VERSION 5.7 ;
BUSBITCHARS "[]" ;
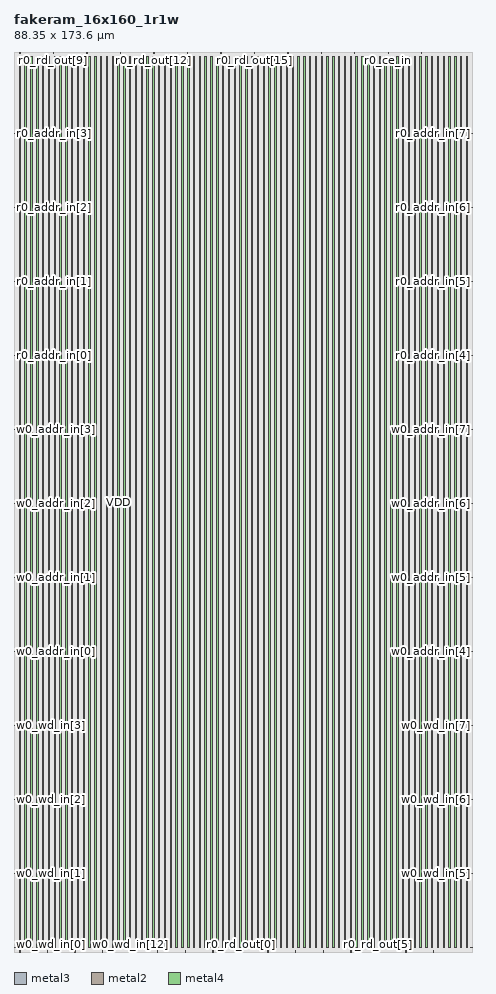
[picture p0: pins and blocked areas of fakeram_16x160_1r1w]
MACRO fakeram_16x160_1r1w
  FOREIGN fakeram_16x160_1r1w 0 0 ;
  SYMMETRY X Y R90 ;
  SIZE 88.350 BY 173.600 ;
  CLASS BLOCK ;
  PIN w0_wd_in[0]
    DIRECTION INPUT ;
    USE SIGNAL ;
    SHAPE ABUTMENT ;
    PORT
      LAYER metal3 ;
      RECT 0.000 0.805 0.210 0.875 ;
    END
  END w0_wd_in[0]
  PIN w0_wd_in[1]
    DIRECTION INPUT ;
    USE SIGNAL ;
    SHAPE ABUTMENT ;
    PORT
      LAYER metal3 ;
      RECT 0.000 15.085 0.210 15.155 ;
    END
  END w0_wd_in[1]
  PIN w0_wd_in[2]
    DIRECTION INPUT ;
    USE SIGNAL ;
    SHAPE ABUTMENT ;
    PORT
      LAYER metal3 ;
      RECT 0.000 29.365 0.210 29.435 ;
    END
  END w0_wd_in[2]
  PIN w0_wd_in[3]
    DIRECTION INPUT ;
    USE SIGNAL ;
    SHAPE ABUTMENT ;
    PORT
      LAYER metal3 ;
      RECT 0.000 43.645 0.210 43.715 ;
    END
  END w0_wd_in[3]
  PIN w0_wd_in[4]
    DIRECTION INPUT ;
    USE SIGNAL ;
    SHAPE ABUTMENT ;
    PORT
      LAYER metal3 ;
      RECT 88.140 0.805 88.350 0.875 ;
    END
  END w0_wd_in[4]
  PIN w0_wd_in[5]
    DIRECTION INPUT ;
    USE SIGNAL ;
    SHAPE ABUTMENT ;
    PORT
      LAYER metal3 ;
      RECT 88.140 15.085 88.350 15.155 ;
    END
  END w0_wd_in[5]
  PIN w0_wd_in[6]
    DIRECTION INPUT ;
    USE SIGNAL ;
    SHAPE ABUTMENT ;
    PORT
      LAYER metal3 ;
      RECT 88.140 29.365 88.350 29.435 ;
    END
  END w0_wd_in[6]
  PIN w0_wd_in[7]
    DIRECTION INPUT ;
    USE SIGNAL ;
    SHAPE ABUTMENT ;
    PORT
      LAYER metal3 ;
      RECT 88.140 43.645 88.350 43.715 ;
    END
  END w0_wd_in[7]
  PIN w0_wd_in[8]
    DIRECTION INPUT ;
    USE SIGNAL ;
    SHAPE ABUTMENT ;
    PORT
      LAYER metal2 ;
      RECT 1.105 0.000 1.175 0.210 ;
    END
  END w0_wd_in[8]
  PIN w0_wd_in[9]
    DIRECTION INPUT ;
    USE SIGNAL ;
    SHAPE ABUTMENT ;
    PORT
      LAYER metal2 ;
      RECT 6.425 0.000 6.495 0.210 ;
    END
  END w0_wd_in[9]
  PIN w0_wd_in[10]
    DIRECTION INPUT ;
    USE SIGNAL ;
    SHAPE ABUTMENT ;
    PORT
      LAYER metal2 ;
      RECT 11.745 0.000 11.815 0.210 ;
    END
  END w0_wd_in[10]
  PIN w0_wd_in[11]
    DIRECTION INPUT ;
    USE SIGNAL ;
    SHAPE ABUTMENT ;
    PORT
      LAYER metal2 ;
      RECT 17.065 0.000 17.135 0.210 ;
    END
  END w0_wd_in[11]
  PIN w0_wd_in[12]
    DIRECTION INPUT ;
    USE SIGNAL ;
    SHAPE ABUTMENT ;
    PORT
      LAYER metal2 ;
      RECT 22.385 0.000 22.455 0.210 ;
    END
  END w0_wd_in[12]
  PIN w0_wd_in[13]
    DIRECTION INPUT ;
    USE SIGNAL ;
    SHAPE ABUTMENT ;
    PORT
      LAYER metal2 ;
      RECT 27.705 0.000 27.775 0.210 ;
    END
  END w0_wd_in[13]
  PIN w0_wd_in[14]
    DIRECTION INPUT ;
    USE SIGNAL ;
    SHAPE ABUTMENT ;
    PORT
      LAYER metal2 ;
      RECT 33.025 0.000 33.095 0.210 ;
    END
  END w0_wd_in[14]
  PIN w0_wd_in[15]
    DIRECTION INPUT ;
    USE SIGNAL ;
    SHAPE ABUTMENT ;
    PORT
      LAYER metal2 ;
      RECT 38.345 0.000 38.415 0.210 ;
    END
  END w0_wd_in[15]
  PIN r0_rd_out[0]
    DIRECTION OUTPUT ;
    USE SIGNAL ;
    SHAPE ABUTMENT ;
    PORT
      LAYER metal2 ;
      RECT 43.665 0.000 43.735 0.210 ;
    END
  END r0_rd_out[0]
  PIN r0_rd_out[1]
    DIRECTION OUTPUT ;
    USE SIGNAL ;
    SHAPE ABUTMENT ;
    PORT
      LAYER metal2 ;
      RECT 48.985 0.000 49.055 0.210 ;
    END
  END r0_rd_out[1]
  PIN r0_rd_out[2]
    DIRECTION OUTPUT ;
    USE SIGNAL ;
    SHAPE ABUTMENT ;
    PORT
      LAYER metal2 ;
      RECT 54.305 0.000 54.375 0.210 ;
    END
  END r0_rd_out[2]
  PIN r0_rd_out[3]
    DIRECTION OUTPUT ;
    USE SIGNAL ;
    SHAPE ABUTMENT ;
    PORT
      LAYER metal2 ;
      RECT 59.625 0.000 59.695 0.210 ;
    END
  END r0_rd_out[3]
  PIN r0_rd_out[4]
    DIRECTION OUTPUT ;
    USE SIGNAL ;
    SHAPE ABUTMENT ;
    PORT
      LAYER metal2 ;
      RECT 64.945 0.000 65.015 0.210 ;
    END
  END r0_rd_out[4]
  PIN r0_rd_out[5]
    DIRECTION OUTPUT ;
    USE SIGNAL ;
    SHAPE ABUTMENT ;
    PORT
      LAYER metal2 ;
      RECT 70.265 0.000 70.335 0.210 ;
    END
  END r0_rd_out[5]
  PIN r0_rd_out[6]
    DIRECTION OUTPUT ;
    USE SIGNAL ;
    SHAPE ABUTMENT ;
    PORT
      LAYER metal2 ;
      RECT 75.585 0.000 75.655 0.210 ;
    END
  END r0_rd_out[6]
  PIN r0_rd_out[7]
    DIRECTION OUTPUT ;
    USE SIGNAL ;
    SHAPE ABUTMENT ;
    PORT
      LAYER metal2 ;
      RECT 80.905 0.000 80.975 0.210 ;
    END
  END r0_rd_out[7]
  PIN r0_rd_out[8]
    DIRECTION OUTPUT ;
    USE SIGNAL ;
    SHAPE ABUTMENT ;
    PORT
      LAYER metal2 ;
      RECT 1.105 173.390 1.175 173.600 ;
    END
  END r0_rd_out[8]
  PIN r0_rd_out[9]
    DIRECTION OUTPUT ;
    USE SIGNAL ;
    SHAPE ABUTMENT ;
    PORT
      LAYER metal2 ;
      RECT 7.565 173.390 7.635 173.600 ;
    END
  END r0_rd_out[9]
  PIN r0_rd_out[10]
    DIRECTION OUTPUT ;
    USE SIGNAL ;
    SHAPE ABUTMENT ;
    PORT
      LAYER metal2 ;
      RECT 14.025 173.390 14.095 173.600 ;
    END
  END r0_rd_out[10]
  PIN r0_rd_out[11]
    DIRECTION OUTPUT ;
    USE SIGNAL ;
    SHAPE ABUTMENT ;
    PORT
      LAYER metal2 ;
      RECT 20.485 173.390 20.555 173.600 ;
    END
  END r0_rd_out[11]
  PIN r0_rd_out[12]
    DIRECTION OUTPUT ;
    USE SIGNAL ;
    SHAPE ABUTMENT ;
    PORT
      LAYER metal2 ;
      RECT 26.945 173.390 27.015 173.600 ;
    END
  END r0_rd_out[12]
  PIN r0_rd_out[13]
    DIRECTION OUTPUT ;
    USE SIGNAL ;
    SHAPE ABUTMENT ;
    PORT
      LAYER metal2 ;
      RECT 33.405 173.390 33.475 173.600 ;
    END
  END r0_rd_out[13]
  PIN r0_rd_out[14]
    DIRECTION OUTPUT ;
    USE SIGNAL ;
    SHAPE ABUTMENT ;
    PORT
      LAYER metal2 ;
      RECT 39.865 173.390 39.935 173.600 ;
    END
  END r0_rd_out[14]
  PIN r0_rd_out[15]
    DIRECTION OUTPUT ;
    USE SIGNAL ;
    SHAPE ABUTMENT ;
    PORT
      LAYER metal2 ;
      RECT 46.325 173.390 46.395 173.600 ;
    END
  END r0_rd_out[15]
  PIN w0_addr_in[0]
    DIRECTION INPUT ;
    USE SIGNAL ;
    SHAPE ABUTMENT ;
    PORT
      LAYER metal3 ;
      RECT 0.000 57.925 0.210 57.995 ;
    END
  END w0_addr_in[0]
  PIN w0_addr_in[1]
    DIRECTION INPUT ;
    USE SIGNAL ;
    SHAPE ABUTMENT ;
    PORT
      LAYER metal3 ;
      RECT 0.000 72.205 0.210 72.275 ;
    END
  END w0_addr_in[1]
  PIN w0_addr_in[2]
    DIRECTION INPUT ;
    USE SIGNAL ;
    SHAPE ABUTMENT ;
    PORT
      LAYER metal3 ;
      RECT 0.000 86.485 0.210 86.555 ;
    END
  END w0_addr_in[2]
  PIN w0_addr_in[3]
    DIRECTION INPUT ;
    USE SIGNAL ;
    SHAPE ABUTMENT ;
    PORT
      LAYER metal3 ;
      RECT 0.000 100.765 0.210 100.835 ;
    END
  END w0_addr_in[3]
  PIN w0_addr_in[4]
    DIRECTION INPUT ;
    USE SIGNAL ;
    SHAPE ABUTMENT ;
    PORT
      LAYER metal3 ;
      RECT 88.140 57.925 88.350 57.995 ;
    END
  END w0_addr_in[4]
  PIN w0_addr_in[5]
    DIRECTION INPUT ;
    USE SIGNAL ;
    SHAPE ABUTMENT ;
    PORT
      LAYER metal3 ;
      RECT 88.140 72.205 88.350 72.275 ;
    END
  END w0_addr_in[5]
  PIN w0_addr_in[6]
    DIRECTION INPUT ;
    USE SIGNAL ;
    SHAPE ABUTMENT ;
    PORT
      LAYER metal3 ;
      RECT 88.140 86.485 88.350 86.555 ;
    END
  END w0_addr_in[6]
  PIN w0_addr_in[7]
    DIRECTION INPUT ;
    USE SIGNAL ;
    SHAPE ABUTMENT ;
    PORT
      LAYER metal3 ;
      RECT 88.140 100.765 88.350 100.835 ;
    END
  END w0_addr_in[7]
  PIN r0_addr_in[0]
    DIRECTION INPUT ;
    USE SIGNAL ;
    SHAPE ABUTMENT ;
    PORT
      LAYER metal3 ;
      RECT 0.000 115.045 0.210 115.115 ;
    END
  END r0_addr_in[0]
  PIN r0_addr_in[1]
    DIRECTION INPUT ;
    USE SIGNAL ;
    SHAPE ABUTMENT ;
    PORT
      LAYER metal3 ;
      RECT 0.000 129.325 0.210 129.395 ;
    END
  END r0_addr_in[1]
  PIN r0_addr_in[2]
    DIRECTION INPUT ;
    USE SIGNAL ;
    SHAPE ABUTMENT ;
    PORT
      LAYER metal3 ;
      RECT 0.000 143.605 0.210 143.675 ;
    END
  END r0_addr_in[2]
  PIN r0_addr_in[3]
    DIRECTION INPUT ;
    USE SIGNAL ;
    SHAPE ABUTMENT ;
    PORT
      LAYER metal3 ;
      RECT 0.000 157.885 0.210 157.955 ;
    END
  END r0_addr_in[3]
  PIN r0_addr_in[4]
    DIRECTION INPUT ;
    USE SIGNAL ;
    SHAPE ABUTMENT ;
    PORT
      LAYER metal3 ;
      RECT 88.140 115.045 88.350 115.115 ;
    END
  END r0_addr_in[4]
  PIN r0_addr_in[5]
    DIRECTION INPUT ;
    USE SIGNAL ;
    SHAPE ABUTMENT ;
    PORT
      LAYER metal3 ;
      RECT 88.140 129.325 88.350 129.395 ;
    END
  END r0_addr_in[5]
  PIN r0_addr_in[6]
    DIRECTION INPUT ;
    USE SIGNAL ;
    SHAPE ABUTMENT ;
    PORT
      LAYER metal3 ;
      RECT 88.140 143.605 88.350 143.675 ;
    END
  END r0_addr_in[6]
  PIN r0_addr_in[7]
    DIRECTION INPUT ;
    USE SIGNAL ;
    SHAPE ABUTMENT ;
    PORT
      LAYER metal3 ;
      RECT 88.140 157.885 88.350 157.955 ;
    END
  END r0_addr_in[7]
  PIN w0_we_in
    DIRECTION INPUT ;
    USE SIGNAL ;
    SHAPE ABUTMENT ;
    PORT
      LAYER metal2 ;
      RECT 52.785 173.390 52.855 173.600 ;
    END
  END w0_we_in
  PIN w0_ce_in
    DIRECTION INPUT ;
    USE SIGNAL ;
    SHAPE ABUTMENT ;
    PORT
      LAYER metal2 ;
      RECT 59.245 173.390 59.315 173.600 ;
    END
  END w0_ce_in
  PIN w0_clk
    DIRECTION INPUT ;
    USE SIGNAL ;
    SHAPE ABUTMENT ;
    PORT
      LAYER metal2 ;
      RECT 65.705 173.390 65.775 173.600 ;
    END
  END w0_clk
  PIN r0_ce_in
    DIRECTION INPUT ;
    USE SIGNAL ;
    SHAPE ABUTMENT ;
    PORT
      LAYER metal2 ;
      RECT 72.165 173.390 72.235 173.600 ;
    END
  END r0_ce_in
  PIN r0_clk
    DIRECTION INPUT ;
    USE SIGNAL ;
    SHAPE ABUTMENT ;
    PORT
      LAYER metal2 ;
      RECT 78.625 173.390 78.695 173.600 ;
    END
  END r0_clk
  PIN VSS
    DIRECTION INOUT ;
    USE GROUND ;
    PORT
      LAYER metal4 ;
      RECT 1.000 0.840 1.280 172.760 ;
      RECT 3.240 0.840 3.520 172.760 ;
      RECT 5.480 0.840 5.760 172.760 ;
      RECT 7.720 0.840 8.000 172.760 ;
      RECT 9.960 0.840 10.240 172.760 ;
      RECT 12.200 0.840 12.480 172.760 ;
      RECT 14.440 0.840 14.720 172.760 ;
      RECT 16.680 0.840 16.960 172.760 ;
      RECT 18.920 0.840 19.200 172.760 ;
      RECT 21.160 0.840 21.440 172.760 ;
      RECT 23.400 0.840 23.680 172.760 ;
      RECT 25.640 0.840 25.920 172.760 ;
      RECT 27.880 0.840 28.160 172.760 ;
      RECT 30.120 0.840 30.400 172.760 ;
      RECT 32.360 0.840 32.640 172.760 ;
      RECT 34.600 0.840 34.880 172.760 ;
      RECT 36.840 0.840 37.120 172.760 ;
      RECT 39.080 0.840 39.360 172.760 ;
      RECT 41.320 0.840 41.600 172.760 ;
      RECT 43.560 0.840 43.840 172.760 ;
      RECT 45.800 0.840 46.080 172.760 ;
      RECT 48.040 0.840 48.320 172.760 ;
      RECT 50.280 0.840 50.560 172.760 ;
      RECT 52.520 0.840 52.800 172.760 ;
      RECT 54.760 0.840 55.040 172.760 ;
      RECT 57.000 0.840 57.280 172.760 ;
      RECT 59.240 0.840 59.520 172.760 ;
      RECT 61.480 0.840 61.760 172.760 ;
      RECT 63.720 0.840 64.000 172.760 ;
      RECT 65.960 0.840 66.240 172.760 ;
      RECT 68.200 0.840 68.480 172.760 ;
      RECT 70.440 0.840 70.720 172.760 ;
      RECT 72.680 0.840 72.960 172.760 ;
      RECT 74.920 0.840 75.200 172.760 ;
      RECT 77.160 0.840 77.440 172.760 ;
      RECT 79.400 0.840 79.680 172.760 ;
      RECT 81.640 0.840 81.920 172.760 ;
      RECT 83.880 0.840 84.160 172.760 ;
      RECT 86.120 0.840 86.400 172.760 ;
    END
  END VSS
  PIN VDD
    DIRECTION INOUT ;
    USE POWER ;
    PORT
      LAYER metal4 ;
      RECT 2.120 0.840 2.400 172.760 ;
      RECT 4.360 0.840 4.640 172.760 ;
      RECT 6.600 0.840 6.880 172.760 ;
      RECT 8.840 0.840 9.120 172.760 ;
      RECT 11.080 0.840 11.360 172.760 ;
      RECT 13.320 0.840 13.600 172.760 ;
      RECT 15.560 0.840 15.840 172.760 ;
      RECT 17.800 0.840 18.080 172.760 ;
      RECT 20.040 0.840 20.320 172.760 ;
      RECT 22.280 0.840 22.560 172.760 ;
      RECT 24.520 0.840 24.800 172.760 ;
      RECT 26.760 0.840 27.040 172.760 ;
      RECT 29.000 0.840 29.280 172.760 ;
      RECT 31.240 0.840 31.520 172.760 ;
      RECT 33.480 0.840 33.760 172.760 ;
      RECT 35.720 0.840 36.000 172.760 ;
      RECT 37.960 0.840 38.240 172.760 ;
      RECT 40.200 0.840 40.480 172.760 ;
      RECT 42.440 0.840 42.720 172.760 ;
      RECT 44.680 0.840 44.960 172.760 ;
      RECT 46.920 0.840 47.200 172.760 ;
      RECT 49.160 0.840 49.440 172.760 ;
      RECT 51.400 0.840 51.680 172.760 ;
      RECT 53.640 0.840 53.920 172.760 ;
      RECT 55.880 0.840 56.160 172.760 ;
      RECT 58.120 0.840 58.400 172.760 ;
      RECT 60.360 0.840 60.640 172.760 ;
      RECT 62.600 0.840 62.880 172.760 ;
      RECT 64.840 0.840 65.120 172.760 ;
      RECT 67.080 0.840 67.360 172.760 ;
      RECT 69.320 0.840 69.600 172.760 ;
      RECT 71.560 0.840 71.840 172.760 ;
      RECT 73.800 0.840 74.080 172.760 ;
      RECT 76.040 0.840 76.320 172.760 ;
      RECT 78.280 0.840 78.560 172.760 ;
      RECT 80.520 0.840 80.800 172.760 ;
      RECT 82.760 0.840 83.040 172.760 ;
      RECT 85.000 0.840 85.280 172.760 ;
      RECT 87.240 0.840 87.520 172.760 ;
    END
  END VDD
  OBS
    LAYER metal1 ;
    RECT 0 0 88.350 173.600 ;
    LAYER metal2 ;
    RECT 0 0 88.350 173.600 ;
    LAYER metal3 ;
    RECT 0 0 88.350 173.600 ;
    LAYER metal4 ;
    RECT 0 0 88.350 173.600 ;
    LAYER OVERLAP ;
    RECT 0 0 88.350 173.600 ;
  END
END fakeram_16x160_1r1w

END LIBRARY
